# =====================================================================
#  SYNTHETIC TECHNOLOGY - THE NUMBERS IN THIS FILE ARE INVENTED.
# =====================================================================
#
# The physical view of `reticle_demo_sc`, the made-up library in
# reticle_sc.lib. Layer pitches, resistances, cell sizes and pin shapes
# were written to be self-consistent and to exercise Reticle's LEF reader
# and its OpenROAD hand-off, not to describe any process. Replace it with
# a real PDK's technology and cell LEF for real results; see docs/asic.md.
VERSION 5.8 ;
BUSBITCHARS "[]" ;
DIVIDERCHAR "/" ;
UNITS
  DATABASE MICRONS 1000 ;
END UNITS
MANUFACTURINGGRID 0.005 ;
CLEARANCEMEASURE EUCLIDEAN ;
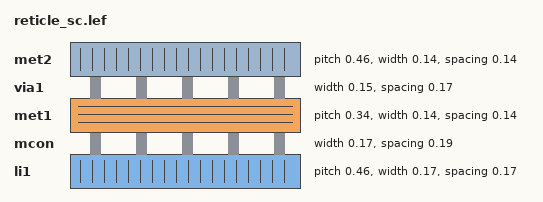
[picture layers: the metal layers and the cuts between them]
LAYER li1
  TYPE ROUTING ;
  DIRECTION VERTICAL ;
  PITCH 0.46 ;
  OFFSET 0.23 ;
  WIDTH 0.17 ;
  SPACING 0.17 ;
  AREA 0.0561 ;
  RESISTANCE RPERSQ 12.2 ;
  CAPACITANCE CPERSQDIST 3.6e-05 ;
END li1
LAYER mcon
  TYPE CUT ;
  WIDTH 0.17 ;
  SPACING 0.19 ;
  RESISTANCE 9.3 ;
END mcon
LAYER met1
  TYPE ROUTING ;
  DIRECTION HORIZONTAL ;
  PITCH 0.34 ;
  OFFSET 0.17 ;
  WIDTH 0.14 ;
  SPACING 0.14 ;
  AREA 0.083 ;
  RESISTANCE RPERSQ 0.125 ;
  CAPACITANCE CPERSQDIST 2.5e-05 ;
END met1
LAYER via1
  TYPE CUT ;
  WIDTH 0.15 ;
  SPACING 0.17 ;
  RESISTANCE 4.5 ;
END via1
LAYER met2
  TYPE ROUTING ;
  DIRECTION VERTICAL ;
  PITCH 0.46 ;
  OFFSET 0.23 ;
  WIDTH 0.14 ;
  SPACING 0.14 ;
  AREA 0.0676 ;
  RESISTANCE RPERSQ 0.125 ;
  CAPACITANCE CPERSQDIST 2.2e-05 ;
END met2
VIA mcon_fixed DEFAULT
  LAYER li1 ;
    RECT -0.085 -0.085 0.085 0.085 ;
  LAYER mcon ;
    RECT -0.085 -0.085 0.085 0.085 ;
  LAYER met1 ;
    RECT -0.085 -0.095 0.085 0.095 ;
END mcon_fixed
VIA via1_fixed DEFAULT
  LAYER met1 ;
    RECT -0.085 -0.085 0.085 0.085 ;
  LAYER via1 ;
    RECT -0.075 -0.075 0.075 0.075 ;
  LAYER met2 ;
    RECT -0.085 -0.085 0.085 0.085 ;
END via1_fixed
SITE retihd
  CLASS CORE ;
  SYMMETRY Y ;
  SIZE 0.46 BY 2.72 ;
END retihd
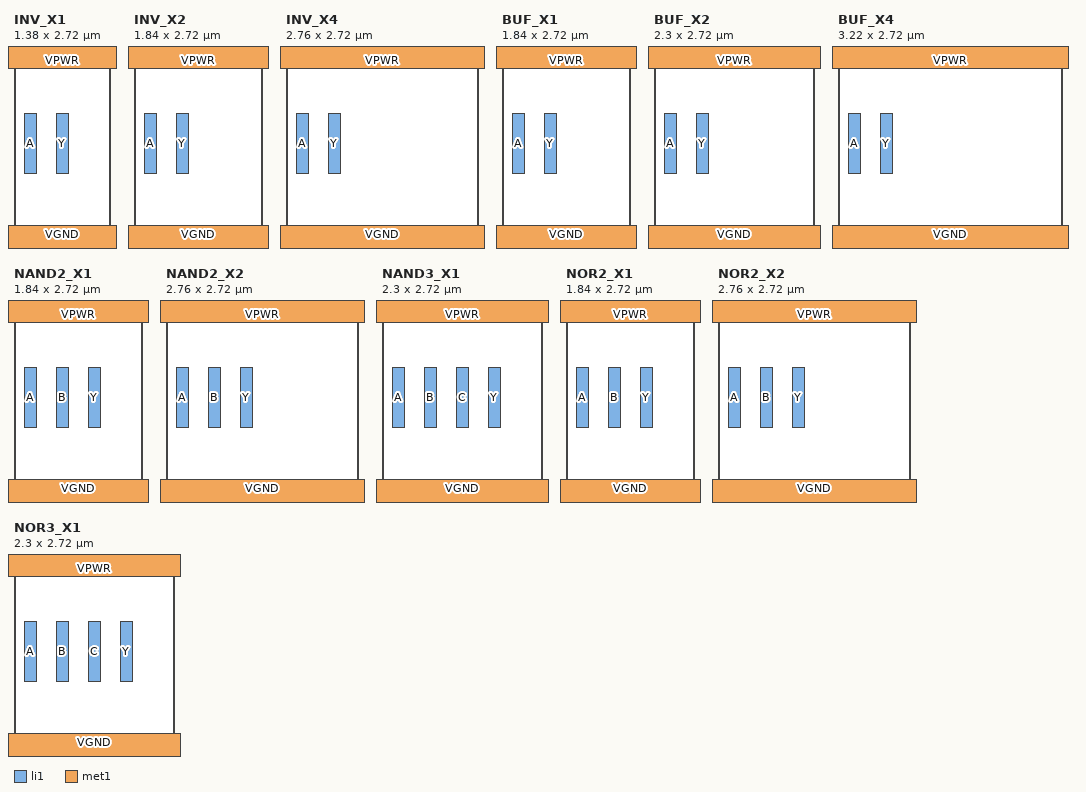
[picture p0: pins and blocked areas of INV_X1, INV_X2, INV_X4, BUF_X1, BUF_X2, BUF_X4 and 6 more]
MACRO INV_X1
  CLASS CORE ;
  FOREIGN INV_X1 0 0 ;
  ORIGIN 0 0 ;
  SIZE 1.38 BY 2.72 ;
  SYMMETRY X Y R90 ;
  SITE retihd ;
  PIN A
    DIRECTION INPUT ;
    USE SIGNAL ;
    PORT
      LAYER li1 ;
        RECT 0.145 0.985 0.315 1.835 ;
    END
  END A
  PIN Y
    DIRECTION OUTPUT ;
    USE SIGNAL ;
    PORT
      LAYER li1 ;
        RECT 0.605 0.985 0.775 1.835 ;
    END
  END Y
  PIN VPWR
    DIRECTION INOUT ;
    USE POWER ;
    SHAPE ABUTMENT ;
    PORT
      LAYER met1 ;
        RECT -0.19 2.48 1.57 2.96 ;
    END
  END VPWR
  PIN VGND
    DIRECTION INOUT ;
    USE GROUND ;
    SHAPE ABUTMENT ;
    PORT
      LAYER met1 ;
        RECT -0.19 -0.24 1.57 0.24 ;
    END
  END VGND
END INV_X1
MACRO INV_X2
  CLASS CORE ;
  FOREIGN INV_X2 0 0 ;
  ORIGIN 0 0 ;
  SIZE 1.84 BY 2.72 ;
  SYMMETRY X Y R90 ;
  SITE retihd ;
  PIN A
    DIRECTION INPUT ;
    USE SIGNAL ;
    PORT
      LAYER li1 ;
        RECT 0.145 0.985 0.315 1.835 ;
    END
  END A
  PIN Y
    DIRECTION OUTPUT ;
    USE SIGNAL ;
    PORT
      LAYER li1 ;
        RECT 0.605 0.985 0.775 1.835 ;
    END
  END Y
  PIN VPWR
    DIRECTION INOUT ;
    USE POWER ;
    SHAPE ABUTMENT ;
    PORT
      LAYER met1 ;
        RECT -0.19 2.48 2.03 2.96 ;
    END
  END VPWR
  PIN VGND
    DIRECTION INOUT ;
    USE GROUND ;
    SHAPE ABUTMENT ;
    PORT
      LAYER met1 ;
        RECT -0.19 -0.24 2.03 0.24 ;
    END
  END VGND
END INV_X2
MACRO INV_X4
  CLASS CORE ;
  FOREIGN INV_X4 0 0 ;
  ORIGIN 0 0 ;
  SIZE 2.76 BY 2.72 ;
  SYMMETRY X Y R90 ;
  SITE retihd ;
  PIN A
    DIRECTION INPUT ;
    USE SIGNAL ;
    PORT
      LAYER li1 ;
        RECT 0.145 0.985 0.315 1.835 ;
    END
  END A
  PIN Y
    DIRECTION OUTPUT ;
    USE SIGNAL ;
    PORT
      LAYER li1 ;
        RECT 0.605 0.985 0.775 1.835 ;
    END
  END Y
  PIN VPWR
    DIRECTION INOUT ;
    USE POWER ;
    SHAPE ABUTMENT ;
    PORT
      LAYER met1 ;
        RECT -0.19 2.48 2.95 2.96 ;
    END
  END VPWR
  PIN VGND
    DIRECTION INOUT ;
    USE GROUND ;
    SHAPE ABUTMENT ;
    PORT
      LAYER met1 ;
        RECT -0.19 -0.24 2.95 0.24 ;
    END
  END VGND
END INV_X4
MACRO BUF_X1
  CLASS CORE ;
  FOREIGN BUF_X1 0 0 ;
  ORIGIN 0 0 ;
  SIZE 1.84 BY 2.72 ;
  SYMMETRY X Y R90 ;
  SITE retihd ;
  PIN A
    DIRECTION INPUT ;
    USE SIGNAL ;
    PORT
      LAYER li1 ;
        RECT 0.145 0.985 0.315 1.835 ;
    END
  END A
  PIN Y
    DIRECTION OUTPUT ;
    USE SIGNAL ;
    PORT
      LAYER li1 ;
        RECT 0.605 0.985 0.775 1.835 ;
    END
  END Y
  PIN VPWR
    DIRECTION INOUT ;
    USE POWER ;
    SHAPE ABUTMENT ;
    PORT
      LAYER met1 ;
        RECT -0.19 2.48 2.03 2.96 ;
    END
  END VPWR
  PIN VGND
    DIRECTION INOUT ;
    USE GROUND ;
    SHAPE ABUTMENT ;
    PORT
      LAYER met1 ;
        RECT -0.19 -0.24 2.03 0.24 ;
    END
  END VGND
END BUF_X1
MACRO BUF_X2
  CLASS CORE ;
  FOREIGN BUF_X2 0 0 ;
  ORIGIN 0 0 ;
  SIZE 2.3 BY 2.72 ;
  SYMMETRY X Y R90 ;
  SITE retihd ;
  PIN A
    DIRECTION INPUT ;
    USE SIGNAL ;
    PORT
      LAYER li1 ;
        RECT 0.145 0.985 0.315 1.835 ;
    END
  END A
  PIN Y
    DIRECTION OUTPUT ;
    USE SIGNAL ;
    PORT
      LAYER li1 ;
        RECT 0.605 0.985 0.775 1.835 ;
    END
  END Y
  PIN VPWR
    DIRECTION INOUT ;
    USE POWER ;
    SHAPE ABUTMENT ;
    PORT
      LAYER met1 ;
        RECT -0.19 2.48 2.49 2.96 ;
    END
  END VPWR
  PIN VGND
    DIRECTION INOUT ;
    USE GROUND ;
    SHAPE ABUTMENT ;
    PORT
      LAYER met1 ;
        RECT -0.19 -0.24 2.49 0.24 ;
    END
  END VGND
END BUF_X2
MACRO BUF_X4
  CLASS CORE ;
  FOREIGN BUF_X4 0 0 ;
  ORIGIN 0 0 ;
  SIZE 3.22 BY 2.72 ;
  SYMMETRY X Y R90 ;
  SITE retihd ;
  PIN A
    DIRECTION INPUT ;
    USE SIGNAL ;
    PORT
      LAYER li1 ;
        RECT 0.145 0.985 0.315 1.835 ;
    END
  END A
  PIN Y
    DIRECTION OUTPUT ;
    USE SIGNAL ;
    PORT
      LAYER li1 ;
        RECT 0.605 0.985 0.775 1.835 ;
    END
  END Y
  PIN VPWR
    DIRECTION INOUT ;
    USE POWER ;
    SHAPE ABUTMENT ;
    PORT
      LAYER met1 ;
        RECT -0.19 2.48 3.41 2.96 ;
    END
  END VPWR
  PIN VGND
    DIRECTION INOUT ;
    USE GROUND ;
    SHAPE ABUTMENT ;
    PORT
      LAYER met1 ;
        RECT -0.19 -0.24 3.41 0.24 ;
    END
  END VGND
END BUF_X4
MACRO NAND2_X1
  CLASS CORE ;
  FOREIGN NAND2_X1 0 0 ;
  ORIGIN 0 0 ;
  SIZE 1.84 BY 2.72 ;
  SYMMETRY X Y R90 ;
  SITE retihd ;
  PIN A
    DIRECTION INPUT ;
    USE SIGNAL ;
    PORT
      LAYER li1 ;
        RECT 0.145 0.985 0.315 1.835 ;
    END
  END A
  PIN B
    DIRECTION INPUT ;
    USE SIGNAL ;
    PORT
      LAYER li1 ;
        RECT 0.605 0.985 0.775 1.835 ;
    END
  END B
  PIN Y
    DIRECTION OUTPUT ;
    USE SIGNAL ;
    PORT
      LAYER li1 ;
        RECT 1.065 0.985 1.235 1.835 ;
    END
  END Y
  PIN VPWR
    DIRECTION INOUT ;
    USE POWER ;
    SHAPE ABUTMENT ;
    PORT
      LAYER met1 ;
        RECT -0.19 2.48 2.03 2.96 ;
    END
  END VPWR
  PIN VGND
    DIRECTION INOUT ;
    USE GROUND ;
    SHAPE ABUTMENT ;
    PORT
      LAYER met1 ;
        RECT -0.19 -0.24 2.03 0.24 ;
    END
  END VGND
END NAND2_X1
MACRO NAND2_X2
  CLASS CORE ;
  FOREIGN NAND2_X2 0 0 ;
  ORIGIN 0 0 ;
  SIZE 2.76 BY 2.72 ;
  SYMMETRY X Y R90 ;
  SITE retihd ;
  PIN A
    DIRECTION INPUT ;
    USE SIGNAL ;
    PORT
      LAYER li1 ;
        RECT 0.145 0.985 0.315 1.835 ;
    END
  END A
  PIN B
    DIRECTION INPUT ;
    USE SIGNAL ;
    PORT
      LAYER li1 ;
        RECT 0.605 0.985 0.775 1.835 ;
    END
  END B
  PIN Y
    DIRECTION OUTPUT ;
    USE SIGNAL ;
    PORT
      LAYER li1 ;
        RECT 1.065 0.985 1.235 1.835 ;
    END
  END Y
  PIN VPWR
    DIRECTION INOUT ;
    USE POWER ;
    SHAPE ABUTMENT ;
    PORT
      LAYER met1 ;
        RECT -0.19 2.48 2.95 2.96 ;
    END
  END VPWR
  PIN VGND
    DIRECTION INOUT ;
    USE GROUND ;
    SHAPE ABUTMENT ;
    PORT
      LAYER met1 ;
        RECT -0.19 -0.24 2.95 0.24 ;
    END
  END VGND
END NAND2_X2
MACRO NAND3_X1
  CLASS CORE ;
  FOREIGN NAND3_X1 0 0 ;
  ORIGIN 0 0 ;
  SIZE 2.3 BY 2.72 ;
  SYMMETRY X Y R90 ;
  SITE retihd ;
  PIN A
    DIRECTION INPUT ;
    USE SIGNAL ;
    PORT
      LAYER li1 ;
        RECT 0.145 0.985 0.315 1.835 ;
    END
  END A
  PIN B
    DIRECTION INPUT ;
    USE SIGNAL ;
    PORT
      LAYER li1 ;
        RECT 0.605 0.985 0.775 1.835 ;
    END
  END B
  PIN C
    DIRECTION INPUT ;
    USE SIGNAL ;
    PORT
      LAYER li1 ;
        RECT 1.065 0.985 1.235 1.835 ;
    END
  END C
  PIN Y
    DIRECTION OUTPUT ;
    USE SIGNAL ;
    PORT
      LAYER li1 ;
        RECT 1.525 0.985 1.695 1.835 ;
    END
  END Y
  PIN VPWR
    DIRECTION INOUT ;
    USE POWER ;
    SHAPE ABUTMENT ;
    PORT
      LAYER met1 ;
        RECT -0.19 2.48 2.49 2.96 ;
    END
  END VPWR
  PIN VGND
    DIRECTION INOUT ;
    USE GROUND ;
    SHAPE ABUTMENT ;
    PORT
      LAYER met1 ;
        RECT -0.19 -0.24 2.49 0.24 ;
    END
  END VGND
END NAND3_X1
MACRO NOR2_X1
  CLASS CORE ;
  FOREIGN NOR2_X1 0 0 ;
  ORIGIN 0 0 ;
  SIZE 1.84 BY 2.72 ;
  SYMMETRY X Y R90 ;
  SITE retihd ;
  PIN A
    DIRECTION INPUT ;
    USE SIGNAL ;
    PORT
      LAYER li1 ;
        RECT 0.145 0.985 0.315 1.835 ;
    END
  END A
  PIN B
    DIRECTION INPUT ;
    USE SIGNAL ;
    PORT
      LAYER li1 ;
        RECT 0.605 0.985 0.775 1.835 ;
    END
  END B
  PIN Y
    DIRECTION OUTPUT ;
    USE SIGNAL ;
    PORT
      LAYER li1 ;
        RECT 1.065 0.985 1.235 1.835 ;
    END
  END Y
  PIN VPWR
    DIRECTION INOUT ;
    USE POWER ;
    SHAPE ABUTMENT ;
    PORT
      LAYER met1 ;
        RECT -0.19 2.48 2.03 2.96 ;
    END
  END VPWR
  PIN VGND
    DIRECTION INOUT ;
    USE GROUND ;
    SHAPE ABUTMENT ;
    PORT
      LAYER met1 ;
        RECT -0.19 -0.24 2.03 0.24 ;
    END
  END VGND
END NOR2_X1
MACRO NOR2_X2
  CLASS CORE ;
  FOREIGN NOR2_X2 0 0 ;
  ORIGIN 0 0 ;
  SIZE 2.76 BY 2.72 ;
  SYMMETRY X Y R90 ;
  SITE retihd ;
  PIN A
    DIRECTION INPUT ;
    USE SIGNAL ;
    PORT
      LAYER li1 ;
        RECT 0.145 0.985 0.315 1.835 ;
    END
  END A
  PIN B
    DIRECTION INPUT ;
    USE SIGNAL ;
    PORT
      LAYER li1 ;
        RECT 0.605 0.985 0.775 1.835 ;
    END
  END B
  PIN Y
    DIRECTION OUTPUT ;
    USE SIGNAL ;
    PORT
      LAYER li1 ;
        RECT 1.065 0.985 1.235 1.835 ;
    END
  END Y
  PIN VPWR
    DIRECTION INOUT ;
    USE POWER ;
    SHAPE ABUTMENT ;
    PORT
      LAYER met1 ;
        RECT -0.19 2.48 2.95 2.96 ;
    END
  END VPWR
  PIN VGND
    DIRECTION INOUT ;
    USE GROUND ;
    SHAPE ABUTMENT ;
    PORT
      LAYER met1 ;
        RECT -0.19 -0.24 2.95 0.24 ;
    END
  END VGND
END NOR2_X2
MACRO NOR3_X1
  CLASS CORE ;
  FOREIGN NOR3_X1 0 0 ;
  ORIGIN 0 0 ;
  SIZE 2.3 BY 2.72 ;
  SYMMETRY X Y R90 ;
  SITE retihd ;
  PIN A
    DIRECTION INPUT ;
    USE SIGNAL ;
    PORT
      LAYER li1 ;
        RECT 0.145 0.985 0.315 1.835 ;
    END
  END A
  PIN B
    DIRECTION INPUT ;
    USE SIGNAL ;
    PORT
      LAYER li1 ;
        RECT 0.605 0.985 0.775 1.835 ;
    END
  END B
  PIN C
    DIRECTION INPUT ;
    USE SIGNAL ;
    PORT
      LAYER li1 ;
        RECT 1.065 0.985 1.235 1.835 ;
    END
  END C
  PIN Y
    DIRECTION OUTPUT ;
    USE SIGNAL ;
    PORT
      LAYER li1 ;
        RECT 1.525 0.985 1.695 1.835 ;
    END
  END Y
  PIN VPWR
    DIRECTION INOUT ;
    USE POWER ;
    SHAPE ABUTMENT ;
    PORT
      LAYER met1 ;
        RECT -0.19 2.48 2.49 2.96 ;
    END
  END VPWR
  PIN VGND
    DIRECTION INOUT ;
    USE GROUND ;
    SHAPE ABUTMENT ;
    PORT
      LAYER met1 ;
        RECT -0.19 -0.24 2.49 0.24 ;
    END
  END VGND
END NOR3_X1
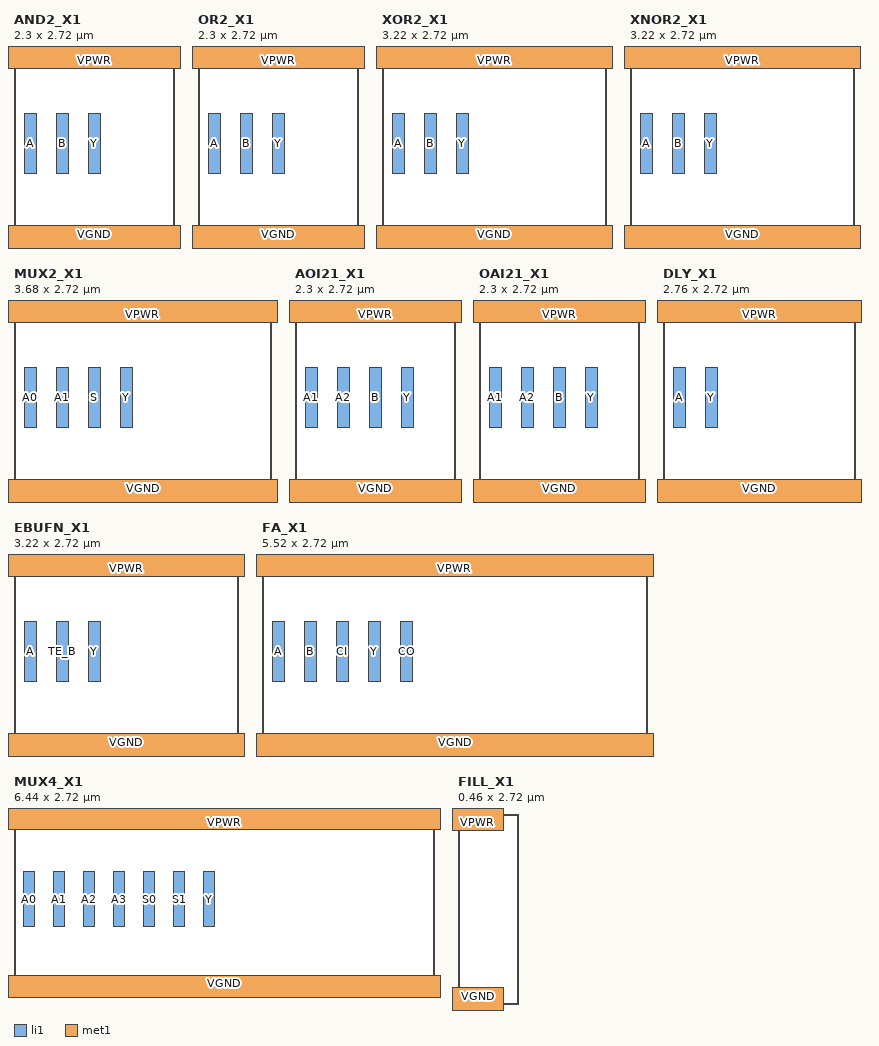
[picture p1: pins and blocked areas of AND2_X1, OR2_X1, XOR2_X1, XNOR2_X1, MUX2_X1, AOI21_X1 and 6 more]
MACRO AND2_X1
  CLASS CORE ;
  FOREIGN AND2_X1 0 0 ;
  ORIGIN 0 0 ;
  SIZE 2.3 BY 2.72 ;
  SYMMETRY X Y R90 ;
  SITE retihd ;
  PIN A
    DIRECTION INPUT ;
    USE SIGNAL ;
    PORT
      LAYER li1 ;
        RECT 0.145 0.985 0.315 1.835 ;
    END
  END A
  PIN B
    DIRECTION INPUT ;
    USE SIGNAL ;
    PORT
      LAYER li1 ;
        RECT 0.605 0.985 0.775 1.835 ;
    END
  END B
  PIN Y
    DIRECTION OUTPUT ;
    USE SIGNAL ;
    PORT
      LAYER li1 ;
        RECT 1.065 0.985 1.235 1.835 ;
    END
  END Y
  PIN VPWR
    DIRECTION INOUT ;
    USE POWER ;
    SHAPE ABUTMENT ;
    PORT
      LAYER met1 ;
        RECT -0.19 2.48 2.49 2.96 ;
    END
  END VPWR
  PIN VGND
    DIRECTION INOUT ;
    USE GROUND ;
    SHAPE ABUTMENT ;
    PORT
      LAYER met1 ;
        RECT -0.19 -0.24 2.49 0.24 ;
    END
  END VGND
END AND2_X1
MACRO OR2_X1
  CLASS CORE ;
  FOREIGN OR2_X1 0 0 ;
  ORIGIN 0 0 ;
  SIZE 2.3 BY 2.72 ;
  SYMMETRY X Y R90 ;
  SITE retihd ;
  PIN A
    DIRECTION INPUT ;
    USE SIGNAL ;
    PORT
      LAYER li1 ;
        RECT 0.145 0.985 0.315 1.835 ;
    END
  END A
  PIN B
    DIRECTION INPUT ;
    USE SIGNAL ;
    PORT
      LAYER li1 ;
        RECT 0.605 0.985 0.775 1.835 ;
    END
  END B
  PIN Y
    DIRECTION OUTPUT ;
    USE SIGNAL ;
    PORT
      LAYER li1 ;
        RECT 1.065 0.985 1.235 1.835 ;
    END
  END Y
  PIN VPWR
    DIRECTION INOUT ;
    USE POWER ;
    SHAPE ABUTMENT ;
    PORT
      LAYER met1 ;
        RECT -0.19 2.48 2.49 2.96 ;
    END
  END VPWR
  PIN VGND
    DIRECTION INOUT ;
    USE GROUND ;
    SHAPE ABUTMENT ;
    PORT
      LAYER met1 ;
        RECT -0.19 -0.24 2.49 0.24 ;
    END
  END VGND
END OR2_X1
MACRO XOR2_X1
  CLASS CORE ;
  FOREIGN XOR2_X1 0 0 ;
  ORIGIN 0 0 ;
  SIZE 3.22 BY 2.72 ;
  SYMMETRY X Y R90 ;
  SITE retihd ;
  PIN A
    DIRECTION INPUT ;
    USE SIGNAL ;
    PORT
      LAYER li1 ;
        RECT 0.145 0.985 0.315 1.835 ;
    END
  END A
  PIN B
    DIRECTION INPUT ;
    USE SIGNAL ;
    PORT
      LAYER li1 ;
        RECT 0.605 0.985 0.775 1.835 ;
    END
  END B
  PIN Y
    DIRECTION OUTPUT ;
    USE SIGNAL ;
    PORT
      LAYER li1 ;
        RECT 1.065 0.985 1.235 1.835 ;
    END
  END Y
  PIN VPWR
    DIRECTION INOUT ;
    USE POWER ;
    SHAPE ABUTMENT ;
    PORT
      LAYER met1 ;
        RECT -0.19 2.48 3.41 2.96 ;
    END
  END VPWR
  PIN VGND
    DIRECTION INOUT ;
    USE GROUND ;
    SHAPE ABUTMENT ;
    PORT
      LAYER met1 ;
        RECT -0.19 -0.24 3.41 0.24 ;
    END
  END VGND
END XOR2_X1
MACRO XNOR2_X1
  CLASS CORE ;
  FOREIGN XNOR2_X1 0 0 ;
  ORIGIN 0 0 ;
  SIZE 3.22 BY 2.72 ;
  SYMMETRY X Y R90 ;
  SITE retihd ;
  PIN A
    DIRECTION INPUT ;
    USE SIGNAL ;
    PORT
      LAYER li1 ;
        RECT 0.145 0.985 0.315 1.835 ;
    END
  END A
  PIN B
    DIRECTION INPUT ;
    USE SIGNAL ;
    PORT
      LAYER li1 ;
        RECT 0.605 0.985 0.775 1.835 ;
    END
  END B
  PIN Y
    DIRECTION OUTPUT ;
    USE SIGNAL ;
    PORT
      LAYER li1 ;
        RECT 1.065 0.985 1.235 1.835 ;
    END
  END Y
  PIN VPWR
    DIRECTION INOUT ;
    USE POWER ;
    SHAPE ABUTMENT ;
    PORT
      LAYER met1 ;
        RECT -0.19 2.48 3.41 2.96 ;
    END
  END VPWR
  PIN VGND
    DIRECTION INOUT ;
    USE GROUND ;
    SHAPE ABUTMENT ;
    PORT
      LAYER met1 ;
        RECT -0.19 -0.24 3.41 0.24 ;
    END
  END VGND
END XNOR2_X1
MACRO MUX2_X1
  CLASS CORE ;
  FOREIGN MUX2_X1 0 0 ;
  ORIGIN 0 0 ;
  SIZE 3.68 BY 2.72 ;
  SYMMETRY X Y R90 ;
  SITE retihd ;
  PIN A0
    DIRECTION INPUT ;
    USE SIGNAL ;
    PORT
      LAYER li1 ;
        RECT 0.145 0.985 0.315 1.835 ;
    END
  END A0
  PIN A1
    DIRECTION INPUT ;
    USE SIGNAL ;
    PORT
      LAYER li1 ;
        RECT 0.605 0.985 0.775 1.835 ;
    END
  END A1
  PIN S
    DIRECTION INPUT ;
    USE SIGNAL ;
    PORT
      LAYER li1 ;
        RECT 1.065 0.985 1.235 1.835 ;
    END
  END S
  PIN Y
    DIRECTION OUTPUT ;
    USE SIGNAL ;
    PORT
      LAYER li1 ;
        RECT 1.525 0.985 1.695 1.835 ;
    END
  END Y
  PIN VPWR
    DIRECTION INOUT ;
    USE POWER ;
    SHAPE ABUTMENT ;
    PORT
      LAYER met1 ;
        RECT -0.19 2.48 3.87 2.96 ;
    END
  END VPWR
  PIN VGND
    DIRECTION INOUT ;
    USE GROUND ;
    SHAPE ABUTMENT ;
    PORT
      LAYER met1 ;
        RECT -0.19 -0.24 3.87 0.24 ;
    END
  END VGND
END MUX2_X1
MACRO AOI21_X1
  CLASS CORE ;
  FOREIGN AOI21_X1 0 0 ;
  ORIGIN 0 0 ;
  SIZE 2.3 BY 2.72 ;
  SYMMETRY X Y R90 ;
  SITE retihd ;
  PIN A1
    DIRECTION INPUT ;
    USE SIGNAL ;
    PORT
      LAYER li1 ;
        RECT 0.145 0.985 0.315 1.835 ;
    END
  END A1
  PIN A2
    DIRECTION INPUT ;
    USE SIGNAL ;
    PORT
      LAYER li1 ;
        RECT 0.605 0.985 0.775 1.835 ;
    END
  END A2
  PIN B
    DIRECTION INPUT ;
    USE SIGNAL ;
    PORT
      LAYER li1 ;
        RECT 1.065 0.985 1.235 1.835 ;
    END
  END B
  PIN Y
    DIRECTION OUTPUT ;
    USE SIGNAL ;
    PORT
      LAYER li1 ;
        RECT 1.525 0.985 1.695 1.835 ;
    END
  END Y
  PIN VPWR
    DIRECTION INOUT ;
    USE POWER ;
    SHAPE ABUTMENT ;
    PORT
      LAYER met1 ;
        RECT -0.19 2.48 2.49 2.96 ;
    END
  END VPWR
  PIN VGND
    DIRECTION INOUT ;
    USE GROUND ;
    SHAPE ABUTMENT ;
    PORT
      LAYER met1 ;
        RECT -0.19 -0.24 2.49 0.24 ;
    END
  END VGND
END AOI21_X1
MACRO OAI21_X1
  CLASS CORE ;
  FOREIGN OAI21_X1 0 0 ;
  ORIGIN 0 0 ;
  SIZE 2.3 BY 2.72 ;
  SYMMETRY X Y R90 ;
  SITE retihd ;
  PIN A1
    DIRECTION INPUT ;
    USE SIGNAL ;
    PORT
      LAYER li1 ;
        RECT 0.145 0.985 0.315 1.835 ;
    END
  END A1
  PIN A2
    DIRECTION INPUT ;
    USE SIGNAL ;
    PORT
      LAYER li1 ;
        RECT 0.605 0.985 0.775 1.835 ;
    END
  END A2
  PIN B
    DIRECTION INPUT ;
    USE SIGNAL ;
    PORT
      LAYER li1 ;
        RECT 1.065 0.985 1.235 1.835 ;
    END
  END B
  PIN Y
    DIRECTION OUTPUT ;
    USE SIGNAL ;
    PORT
      LAYER li1 ;
        RECT 1.525 0.985 1.695 1.835 ;
    END
  END Y
  PIN VPWR
    DIRECTION INOUT ;
    USE POWER ;
    SHAPE ABUTMENT ;
    PORT
      LAYER met1 ;
        RECT -0.19 2.48 2.49 2.96 ;
    END
  END VPWR
  PIN VGND
    DIRECTION INOUT ;
    USE GROUND ;
    SHAPE ABUTMENT ;
    PORT
      LAYER met1 ;
        RECT -0.19 -0.24 2.49 0.24 ;
    END
  END VGND
END OAI21_X1
MACRO DLY_X1
  CLASS CORE ;
  FOREIGN DLY_X1 0 0 ;
  ORIGIN 0 0 ;
  SIZE 2.76 BY 2.72 ;
  SYMMETRY X Y R90 ;
  SITE retihd ;
  PIN A
    DIRECTION INPUT ;
    USE SIGNAL ;
    PORT
      LAYER li1 ;
        RECT 0.145 0.985 0.315 1.835 ;
    END
  END A
  PIN Y
    DIRECTION OUTPUT ;
    USE SIGNAL ;
    PORT
      LAYER li1 ;
        RECT 0.605 0.985 0.775 1.835 ;
    END
  END Y
  PIN VPWR
    DIRECTION INOUT ;
    USE POWER ;
    SHAPE ABUTMENT ;
    PORT
      LAYER met1 ;
        RECT -0.19 2.48 2.95 2.96 ;
    END
  END VPWR
  PIN VGND
    DIRECTION INOUT ;
    USE GROUND ;
    SHAPE ABUTMENT ;
    PORT
      LAYER met1 ;
        RECT -0.19 -0.24 2.95 0.24 ;
    END
  END VGND
END DLY_X1
MACRO EBUFN_X1
  CLASS CORE ;
  FOREIGN EBUFN_X1 0 0 ;
  ORIGIN 0 0 ;
  SIZE 3.22 BY 2.72 ;
  SYMMETRY X Y R90 ;
  SITE retihd ;
  PIN A
    DIRECTION INPUT ;
    USE SIGNAL ;
    PORT
      LAYER li1 ;
        RECT 0.145 0.985 0.315 1.835 ;
    END
  END A
  PIN TE_B
    DIRECTION INPUT ;
    USE SIGNAL ;
    PORT
      LAYER li1 ;
        RECT 0.605 0.985 0.775 1.835 ;
    END
  END TE_B
  PIN Y
    DIRECTION OUTPUT ;
    USE SIGNAL ;
    PORT
      LAYER li1 ;
        RECT 1.065 0.985 1.235 1.835 ;
    END
  END Y
  PIN VPWR
    DIRECTION INOUT ;
    USE POWER ;
    SHAPE ABUTMENT ;
    PORT
      LAYER met1 ;
        RECT -0.19 2.48 3.41 2.96 ;
    END
  END VPWR
  PIN VGND
    DIRECTION INOUT ;
    USE GROUND ;
    SHAPE ABUTMENT ;
    PORT
      LAYER met1 ;
        RECT -0.19 -0.24 3.41 0.24 ;
    END
  END VGND
END EBUFN_X1
MACRO FA_X1
  CLASS CORE ;
  FOREIGN FA_X1 0 0 ;
  ORIGIN 0 0 ;
  SIZE 5.52 BY 2.72 ;
  SYMMETRY X Y R90 ;
  SITE retihd ;
  PIN A
    DIRECTION INPUT ;
    USE SIGNAL ;
    PORT
      LAYER li1 ;
        RECT 0.145 0.985 0.315 1.835 ;
    END
  END A
  PIN B
    DIRECTION INPUT ;
    USE SIGNAL ;
    PORT
      LAYER li1 ;
        RECT 0.605 0.985 0.775 1.835 ;
    END
  END B
  PIN CI
    DIRECTION INPUT ;
    USE SIGNAL ;
    PORT
      LAYER li1 ;
        RECT 1.065 0.985 1.235 1.835 ;
    END
  END CI
  PIN Y
    DIRECTION OUTPUT ;
    USE SIGNAL ;
    PORT
      LAYER li1 ;
        RECT 1.525 0.985 1.695 1.835 ;
    END
  END Y
  PIN CO
    DIRECTION OUTPUT ;
    USE SIGNAL ;
    PORT
      LAYER li1 ;
        RECT 1.985 0.985 2.155 1.835 ;
    END
  END CO
  PIN VPWR
    DIRECTION INOUT ;
    USE POWER ;
    SHAPE ABUTMENT ;
    PORT
      LAYER met1 ;
        RECT -0.19 2.48 5.71 2.96 ;
    END
  END VPWR
  PIN VGND
    DIRECTION INOUT ;
    USE GROUND ;
    SHAPE ABUTMENT ;
    PORT
      LAYER met1 ;
        RECT -0.19 -0.24 5.71 0.24 ;
    END
  END VGND
END FA_X1
MACRO MUX4_X1
  CLASS CORE ;
  FOREIGN MUX4_X1 0 0 ;
  ORIGIN 0 0 ;
  SIZE 6.44 BY 2.72 ;
  SYMMETRY X Y R90 ;
  SITE retihd ;
  PIN A0
    DIRECTION INPUT ;
    USE SIGNAL ;
    PORT
      LAYER li1 ;
        RECT 0.145 0.985 0.315 1.835 ;
    END
  END A0
  PIN A1
    DIRECTION INPUT ;
    USE SIGNAL ;
    PORT
      LAYER li1 ;
        RECT 0.605 0.985 0.775 1.835 ;
    END
  END A1
  PIN A2
    DIRECTION INPUT ;
    USE SIGNAL ;
    PORT
      LAYER li1 ;
        RECT 1.065 0.985 1.235 1.835 ;
    END
  END A2
  PIN A3
    DIRECTION INPUT ;
    USE SIGNAL ;
    PORT
      LAYER li1 ;
        RECT 1.525 0.985 1.695 1.835 ;
    END
  END A3
  PIN S0
    DIRECTION INPUT ;
    USE SIGNAL ;
    PORT
      LAYER li1 ;
        RECT 1.985 0.985 2.155 1.835 ;
    END
  END S0
  PIN S1
    DIRECTION INPUT ;
    USE SIGNAL ;
    PORT
      LAYER li1 ;
        RECT 2.445 0.985 2.615 1.835 ;
    END
  END S1
  PIN Y
    DIRECTION OUTPUT ;
    USE SIGNAL ;
    PORT
      LAYER li1 ;
        RECT 2.905 0.985 3.075 1.835 ;
    END
  END Y
  PIN VPWR
    DIRECTION INOUT ;
    USE POWER ;
    SHAPE ABUTMENT ;
    PORT
      LAYER met1 ;
        RECT -0.19 2.48 6.63 2.96 ;
    END
  END VPWR
  PIN VGND
    DIRECTION INOUT ;
    USE GROUND ;
    SHAPE ABUTMENT ;
    PORT
      LAYER met1 ;
        RECT -0.19 -0.24 6.63 0.24 ;
    END
  END VGND
END MUX4_X1
MACRO FILL_X1
  CLASS CORE ;
  FOREIGN FILL_X1 0 0 ;
  ORIGIN 0 0 ;
  SIZE 0.46 BY 2.72 ;
  SYMMETRY X Y R90 ;
  SITE retihd ;
  PIN VPWR
    DIRECTION INOUT ;
    USE POWER ;
    SHAPE ABUTMENT ;
    PORT
      LAYER met1 ;
        RECT -0.19 2.48 0.65 2.96 ;
    END
  END VPWR
  PIN VGND
    DIRECTION INOUT ;
    USE GROUND ;
    SHAPE ABUTMENT ;
    PORT
      LAYER met1 ;
        RECT -0.19 -0.24 0.65 0.24 ;
    END
  END VGND
END FILL_X1
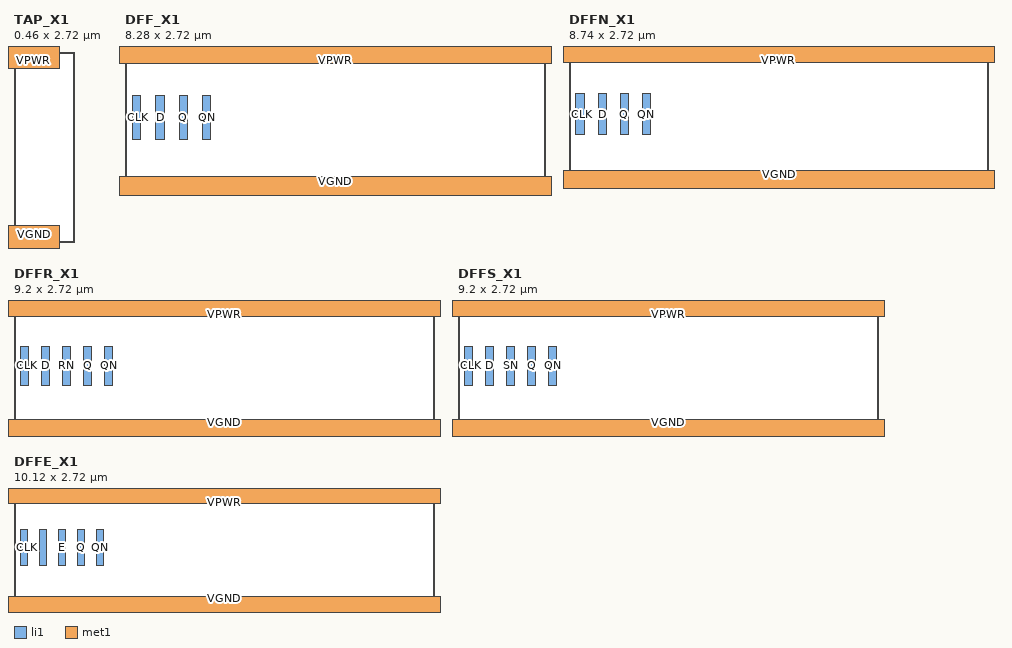
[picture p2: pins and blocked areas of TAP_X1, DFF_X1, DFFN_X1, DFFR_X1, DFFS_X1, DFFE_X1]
MACRO TAP_X1
  CLASS CORE ;
  FOREIGN TAP_X1 0 0 ;
  ORIGIN 0 0 ;
  SIZE 0.46 BY 2.72 ;
  SYMMETRY X Y R90 ;
  SITE retihd ;
  PIN VPWR
    DIRECTION INOUT ;
    USE POWER ;
    SHAPE ABUTMENT ;
    PORT
      LAYER met1 ;
        RECT -0.19 2.48 0.65 2.96 ;
    END
  END VPWR
  PIN VGND
    DIRECTION INOUT ;
    USE GROUND ;
    SHAPE ABUTMENT ;
    PORT
      LAYER met1 ;
        RECT -0.19 -0.24 0.65 0.24 ;
    END
  END VGND
END TAP_X1
MACRO DFF_X1
  CLASS CORE ;
  FOREIGN DFF_X1 0 0 ;
  ORIGIN 0 0 ;
  SIZE 8.28 BY 2.72 ;
  SYMMETRY X Y R90 ;
  SITE retihd ;
  PIN CLK
    DIRECTION INPUT ;
    USE SIGNAL ;
    PORT
      LAYER li1 ;
        RECT 0.145 0.985 0.315 1.835 ;
    END
  END CLK
  PIN D
    DIRECTION INPUT ;
    USE SIGNAL ;
    PORT
      LAYER li1 ;
        RECT 0.605 0.985 0.775 1.835 ;
    END
  END D
  PIN Q
    DIRECTION OUTPUT ;
    USE SIGNAL ;
    PORT
      LAYER li1 ;
        RECT 1.065 0.985 1.235 1.835 ;
    END
  END Q
  PIN QN
    DIRECTION OUTPUT ;
    USE SIGNAL ;
    PORT
      LAYER li1 ;
        RECT 1.525 0.985 1.695 1.835 ;
    END
  END QN
  PIN VPWR
    DIRECTION INOUT ;
    USE POWER ;
    SHAPE ABUTMENT ;
    PORT
      LAYER met1 ;
        RECT -0.19 2.48 8.47 2.96 ;
    END
  END VPWR
  PIN VGND
    DIRECTION INOUT ;
    USE GROUND ;
    SHAPE ABUTMENT ;
    PORT
      LAYER met1 ;
        RECT -0.19 -0.24 8.47 0.24 ;
    END
  END VGND
END DFF_X1
MACRO DFFN_X1
  CLASS CORE ;
  FOREIGN DFFN_X1 0 0 ;
  ORIGIN 0 0 ;
  SIZE 8.74 BY 2.72 ;
  SYMMETRY X Y R90 ;
  SITE retihd ;
  PIN CLK
    DIRECTION INPUT ;
    USE SIGNAL ;
    PORT
      LAYER li1 ;
        RECT 0.145 0.985 0.315 1.835 ;
    END
  END CLK
  PIN D
    DIRECTION INPUT ;
    USE SIGNAL ;
    PORT
      LAYER li1 ;
        RECT 0.605 0.985 0.775 1.835 ;
    END
  END D
  PIN Q
    DIRECTION OUTPUT ;
    USE SIGNAL ;
    PORT
      LAYER li1 ;
        RECT 1.065 0.985 1.235 1.835 ;
    END
  END Q
  PIN QN
    DIRECTION OUTPUT ;
    USE SIGNAL ;
    PORT
      LAYER li1 ;
        RECT 1.525 0.985 1.695 1.835 ;
    END
  END QN
  PIN VPWR
    DIRECTION INOUT ;
    USE POWER ;
    SHAPE ABUTMENT ;
    PORT
      LAYER met1 ;
        RECT -0.19 2.48 8.93 2.96 ;
    END
  END VPWR
  PIN VGND
    DIRECTION INOUT ;
    USE GROUND ;
    SHAPE ABUTMENT ;
    PORT
      LAYER met1 ;
        RECT -0.19 -0.24 8.93 0.24 ;
    END
  END VGND
END DFFN_X1
MACRO DFFR_X1
  CLASS CORE ;
  FOREIGN DFFR_X1 0 0 ;
  ORIGIN 0 0 ;
  SIZE 9.2 BY 2.72 ;
  SYMMETRY X Y R90 ;
  SITE retihd ;
  PIN CLK
    DIRECTION INPUT ;
    USE SIGNAL ;
    PORT
      LAYER li1 ;
        RECT 0.145 0.985 0.315 1.835 ;
    END
  END CLK
  PIN D
    DIRECTION INPUT ;
    USE SIGNAL ;
    PORT
      LAYER li1 ;
        RECT 0.605 0.985 0.775 1.835 ;
    END
  END D
  PIN RN
    DIRECTION INPUT ;
    USE SIGNAL ;
    PORT
      LAYER li1 ;
        RECT 1.065 0.985 1.235 1.835 ;
    END
  END RN
  PIN Q
    DIRECTION OUTPUT ;
    USE SIGNAL ;
    PORT
      LAYER li1 ;
        RECT 1.525 0.985 1.695 1.835 ;
    END
  END Q
  PIN QN
    DIRECTION OUTPUT ;
    USE SIGNAL ;
    PORT
      LAYER li1 ;
        RECT 1.985 0.985 2.155 1.835 ;
    END
  END QN
  PIN VPWR
    DIRECTION INOUT ;
    USE POWER ;
    SHAPE ABUTMENT ;
    PORT
      LAYER met1 ;
        RECT -0.19 2.48 9.39 2.96 ;
    END
  END VPWR
  PIN VGND
    DIRECTION INOUT ;
    USE GROUND ;
    SHAPE ABUTMENT ;
    PORT
      LAYER met1 ;
        RECT -0.19 -0.24 9.39 0.24 ;
    END
  END VGND
END DFFR_X1
MACRO DFFS_X1
  CLASS CORE ;
  FOREIGN DFFS_X1 0 0 ;
  ORIGIN 0 0 ;
  SIZE 9.2 BY 2.72 ;
  SYMMETRY X Y R90 ;
  SITE retihd ;
  PIN CLK
    DIRECTION INPUT ;
    USE SIGNAL ;
    PORT
      LAYER li1 ;
        RECT 0.145 0.985 0.315 1.835 ;
    END
  END CLK
  PIN D
    DIRECTION INPUT ;
    USE SIGNAL ;
    PORT
      LAYER li1 ;
        RECT 0.605 0.985 0.775 1.835 ;
    END
  END D
  PIN SN
    DIRECTION INPUT ;
    USE SIGNAL ;
    PORT
      LAYER li1 ;
        RECT 1.065 0.985 1.235 1.835 ;
    END
  END SN
  PIN Q
    DIRECTION OUTPUT ;
    USE SIGNAL ;
    PORT
      LAYER li1 ;
        RECT 1.525 0.985 1.695 1.835 ;
    END
  END Q
  PIN QN
    DIRECTION OUTPUT ;
    USE SIGNAL ;
    PORT
      LAYER li1 ;
        RECT 1.985 0.985 2.155 1.835 ;
    END
  END QN
  PIN VPWR
    DIRECTION INOUT ;
    USE POWER ;
    SHAPE ABUTMENT ;
    PORT
      LAYER met1 ;
        RECT -0.19 2.48 9.39 2.96 ;
    END
  END VPWR
  PIN VGND
    DIRECTION INOUT ;
    USE GROUND ;
    SHAPE ABUTMENT ;
    PORT
      LAYER met1 ;
        RECT -0.19 -0.24 9.39 0.24 ;
    END
  END VGND
END DFFS_X1
MACRO DFFE_X1
  CLASS CORE ;
  FOREIGN DFFE_X1 0 0 ;
  ORIGIN 0 0 ;
  SIZE 10.12 BY 2.72 ;
  SYMMETRY X Y R90 ;
  SITE retihd ;
  PIN CLK
    DIRECTION INPUT ;
    USE SIGNAL ;
    PORT
      LAYER li1 ;
        RECT 0.145 0.985 0.315 1.835 ;
    END
  END CLK
  PIN D
    DIRECTION INPUT ;
    USE SIGNAL ;
    PORT
      LAYER li1 ;
        RECT 0.605 0.985 0.775 1.835 ;
    END
  END D
  PIN E
    DIRECTION INPUT ;
    USE SIGNAL ;
    PORT
      LAYER li1 ;
        RECT 1.065 0.985 1.235 1.835 ;
    END
  END E
  PIN Q
    DIRECTION OUTPUT ;
    USE SIGNAL ;
    PORT
      LAYER li1 ;
        RECT 1.525 0.985 1.695 1.835 ;
    END
  END Q
  PIN QN
    DIRECTION OUTPUT ;
    USE SIGNAL ;
    PORT
      LAYER li1 ;
        RECT 1.985 0.985 2.155 1.835 ;
    END
  END QN
  PIN VPWR
    DIRECTION INOUT ;
    USE POWER ;
    SHAPE ABUTMENT ;
    PORT
      LAYER met1 ;
        RECT -0.19 2.48 10.31 2.96 ;
    END
  END VPWR
  PIN VGND
    DIRECTION INOUT ;
    USE GROUND ;
    SHAPE ABUTMENT ;
    PORT
      LAYER met1 ;
        RECT -0.19 -0.24 10.31 0.24 ;
    END
  END VGND
END DFFE_X1
END LIBRARY
